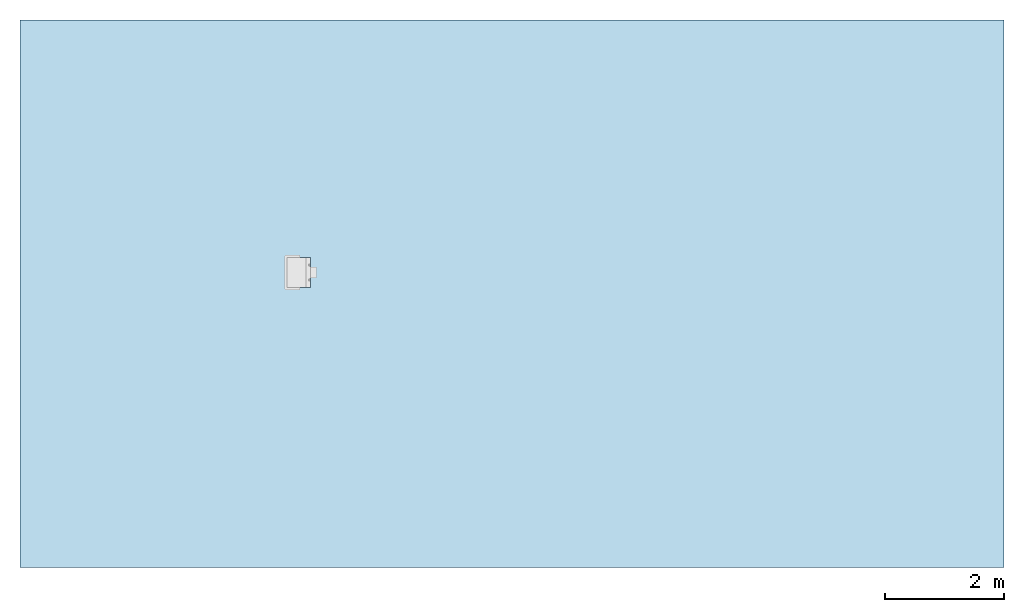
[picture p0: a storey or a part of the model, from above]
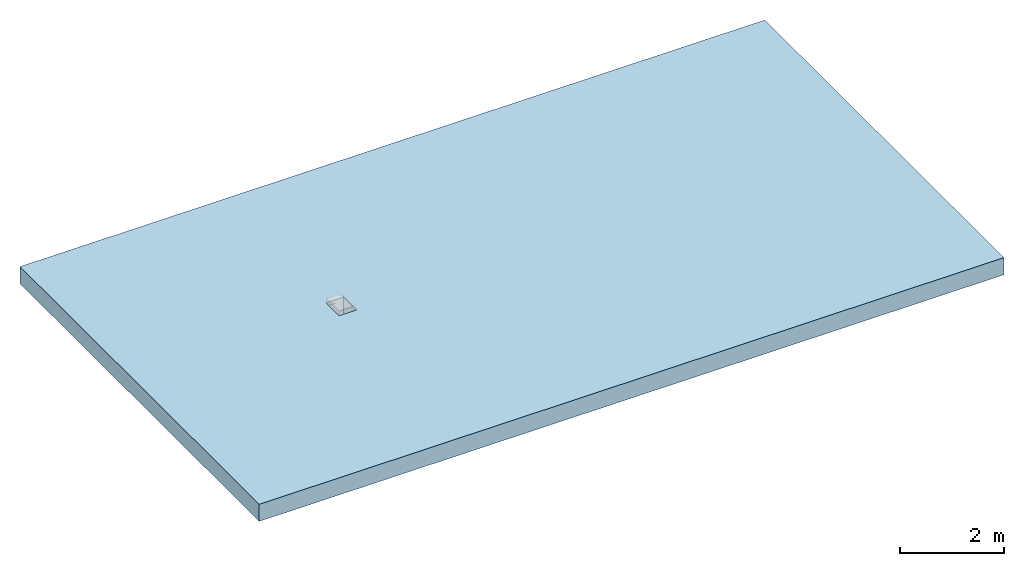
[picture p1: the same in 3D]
Properties of the parts of a building model (IFC2X3)

# File
Description: ViewDefinition [CoordinationView]
File name: 4979 - Top and roddable deep base assembly KDSP612RE.ifc
Time: 2013-09-04T10:22:30
Written by: Autodesk Revit 2013
Made in: 20120221_2030(x64)

# IfcProject, Project Number
LongName: Project Name; Phase: Project Status

# IfcSite, Default
RefLatitude: 42, 21, 30, 344238; RefLongitude: -71, -3, -35, -194702; RefElevation: 0 mm

# IfcBuilding
Pset_BuildingCommon - NumberOfStoreys: 1
Other - Project Issue Date: Issue Date; Project Number: Project Number; Project Status: Project Status; Project Name: Project Name; Client Name: Owner; Project Address: ## Street City, State Zip

# IfcBuildingStorey, Level 1
LongName: Level 1; Elevation: 0 mm
Constraints - Elevation Base: 0; Elevation: 0 mm
Graphics - Color: 0; Line Weight: 1; Line Pattern: Center; Symbol at End 2 Default: yes; Symbol at End 1 Default: no; Symbol: M_Level Head - Circle: M_Level Head - Circle
Identity Data - Name: Level 1; Structural: no; Building Story: yes
Dimensions - Computation Height: 0 mm

# IfcBuildingElementProxy: 4979 - Top and roddable deep base assembly KDSP612RE, Civil-Drainage-Channel-ACO-KerbDrain-SP Gully unit:4979 - Top and roddable deep base assembly KDSP612RE:4979 - Top and roddable deep base assembly KDSP612RE:312482
In: Level 1
Material: Ductile Iron, ACO Polmer Concrete., Gully
Materials and Finishes - Gully Cover/Frame Material: Ductile Iron; Gully Base Material: Vienite® Synthetic Resin Concrete; Gully Cover/Frame Colour: Black; Gully Cover/Frame Finish: Water Based Paint Coating; Gully Base Colour: Brown
Phasing - Phase Created: New Construction
Constraints - Moves With Nearby Elements: no; Level: Level: Level 1
Dimensions - Volume: 43448307 mm3; Gully Connector Void End: 2005 mm; Top and bottom 4979 void depth: 462.065 mm; Deep Base Void Depth: 405 mm; Gully Connector Void Start: 2000 mm; Shallow Base Depth: 6000 mm
Pset_BuildingElementProxyCommon - Reference: 4979 - Top and roddable deep base assembly KDSP612RE
Data - Invert Depth: 750/780mm; Hydraulic Performance: http://www.aco.co.uk/download.php?id=120; Load Class: A 15 - D 400; Drainage Slot Intake area: 14592mm²/m; Product Dimensions: 500mm x 390mm x 1025mm (LxWxH); ACO Hydraulic Design Software: http://www.acodesign.co.uk; Installation - Concrete Grade: Refer to brochure; Product Standard: BS EN 1433:2002, CE marked, Kitemarked; Product Weight: 119.9 Kg; Drainage Slot Width: 50mm
Construction - Shallow base: no; Top assembly: yes; Deep Base: yes; Top and road gully connector: no; Top and roddable deep base assembly KDSP612RE: yes
Identity Data - Product brochure: http://www.aco.co.uk/download.php?id=120; Type Comments: ACO KerbDrain Splayed Gully Units - Top & Roddable Deep Base Assembly KDSP612RE; Price: POA - contact ACO; URL: www.aco.co.uk; Maintenance guidelines: http://www.aco.co.uk/download.php?id=120; OmniClass Title: Rainwater Removal; Manufacturer: ACO Technologies plc - ACO Water Management Division; e-mail Sales: customersupport@aco.co.uk; Telephone: +44 (0)1462 816666; Product Page URL: http://www.aco.co.uk/product_detail.php?id=3; Installation guidelines: http://www.aco.co.uk/download.php?id=120; Address: ACO Business Park, Hitchin Road, Shefford, Bedfordshire, United Kingdom SG17 5TE; Model Description: Combined kerb and drainage system; OmniClass Number: 23.70.50.24; Model: ACO KerbDrain Splayed Gully Units; Assembly Description: Rain Water Drainage; e-mail Technical: technical@aco.co.uk; Cost: 0; Assembly Code: D2040; Fax: +44 (0)1462 815895; Product Code: 4979
Other - Revision: 1; CreatedBy: www.aco.co.uk
General - TagNumber: 0.000000; SerialNumber: 0.000000
Green Building Properties - Gully Base Recyclable: Fully recyclable; Gully Cover/Frame Recyclable: Fully recyclable; Gully Cover/Frame Recycled Material Content: Between 40% - 90%; Gully Base Recycled Material Content: 20% minimum

# IfcOpeningElement: Opening (3)
In: Level 1
Structural - Enable Analytical Model: no; Structural: no
Dimensions - Volume: 60509762589 mm3; Perimeter: 51360 mm; Area: 151275000 mm2; Thickness: 400 mm
Phasing - Phase Created: New Construction
Constraints - Room Bounding: yes; Height Offset From Level: 0 mm; Level: Level: Level 1; Related to Mass: no
Analytical Properties - Roughness: 1; Absorptance: 0.1
Construction - Default Thickness: 400 mm; Function: 0
Graphics - Coarse Scale Fill Color: 0
Materials and Finishes - Structural Material: Plant

# IfcSlab: Floor:Generic Floor - 400mm, Floor:Generic Floor - 400mm:193825
In: Level 1
PredefinedType: FLOOR; Material: Plant 400 mm
Structural - Enable Analytical Model: no; Structural: no
Dimensions - Volume: 60509762589 mm3; Perimeter: 51360 mm; Area: 151275000 mm2; Thickness: 400 mm
Phasing - Phase Created: New Construction
Constraints - Room Bounding: yes; Height Offset From Level: 0 mm; Level: Level: Level 1; Related to Mass: no
Pset_SlabCommon - Reference: Generic Floor - 400mm; IsExternal: no; LoadBearing: yes
Analytical Properties - Roughness: 1; Absorptance: 0.1
Construction - Default Thickness: 400 mm; Function: 0
Graphics - Coarse Scale Fill Color: 0
Materials and Finishes - Structural Material: Plant
